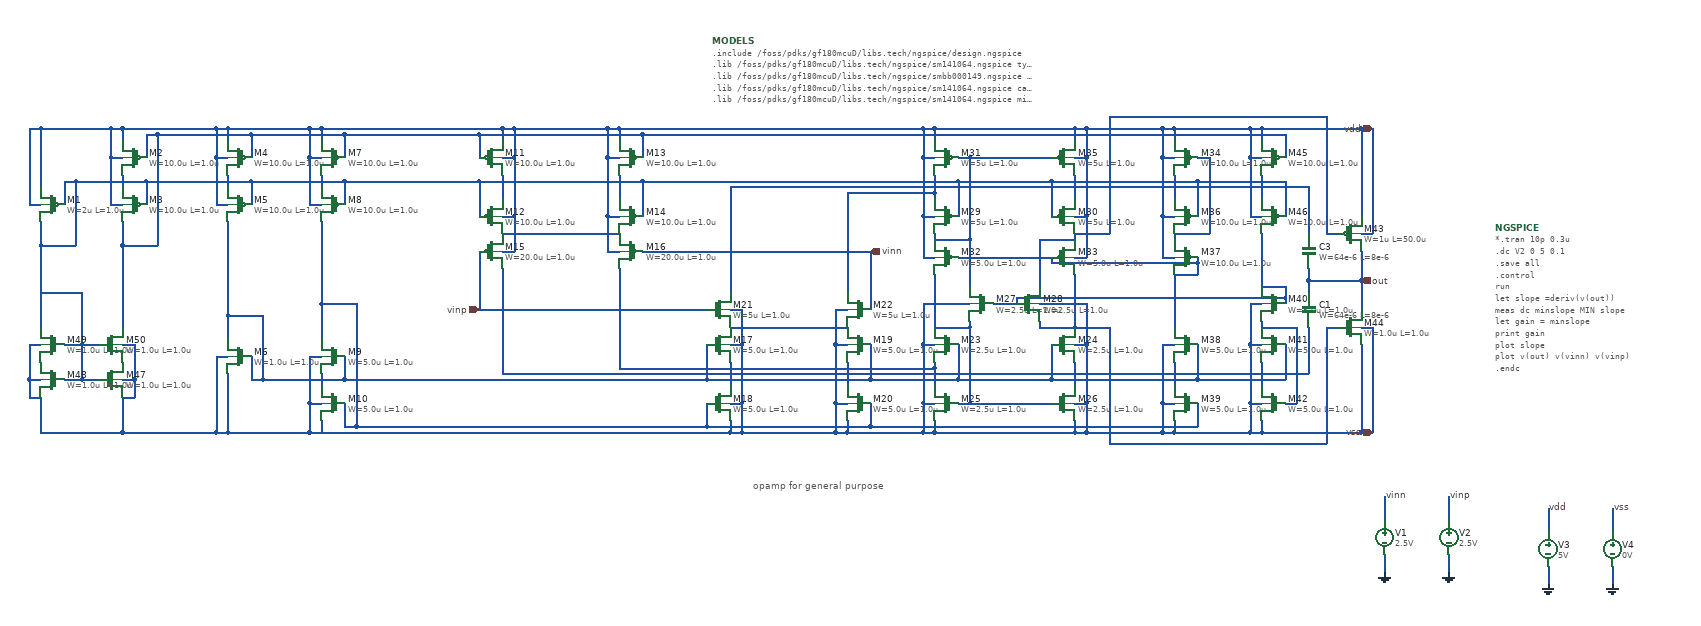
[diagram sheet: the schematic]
v {xschem version=3.4.8RC file_version=1.3}
G {}
K {}
V {}
S {}
F {}
E {}
P 4 1 -1280 220 {}
T {opamp for general purpose} -630 450 2 0 0.4 0.4 {}
N -1060 60 -1040 60 {
lab=vdd}
N -880 60 -860 60 {
lab=vdd}
N -1060 -150 -1060 -130 {
lab=vdd}
N -1060 -100 -1040 -100 {
lab=vdd}
N -1100 -140 -1100 -100 {
lab=#net1}
N -340 320 -340 370 {
lab=vss}
N -340 320 -320 320 {
lab=vss}
N -320 350 -320 370 {
lab=vss}
N -320 -150 -320 -130 {
lab=vdd}
N -340 -100 -320 -100 {
lab=vdd}
N -80 -150 -80 -130 {
lab=vdd}
N -80 -100 -60 -100 {
lab=vdd}
N -60 -100 -60 0 {
lab=vdd}
N -80 320 -60 320 {
lab=vss}
N -80 350 -80 370 {
lab=vss}
N -1100 60 -1100 160 {
lab=vinp}
N -490 160 -470 160 {
lab=vss}
N -670 220 -650 220 {
lab=vss}
N -650 320 -650 370 {
lab=vss}
N -670 320 -650 320 {
lab=vss}
N -670 250 -670 290 {
lab=#net2}
N -670 350 -670 370 {
lab=vss}
N -710 320 -710 360 {
lab=#net3}
N -710 220 -710 280 {
lab=#net4}
N -1060 0 -1040 0 {
lab=vdd}
N -1060 -70 -1060 -30 {
lab=#net5}
N -1100 -60 -1100 0 {
lab=#net6}
N -340 -100 -340 0 {
lab=vdd}
N -340 0 -320 0 {
lab=vdd}
N -320 -40 -320 -30 {
lab=#net7}
N -340 220 -320 220 {
lab=vss}
N -340 220 -340 320 {
lab=vss}
N -320 260 -320 290 {
lab=#net8}
N -80 270 -80 290 {
lab=#net9}
N -80 220 -60 220 {
lab=vss}
N -820 60 -430 60 {
lab=vinn}
N -430 60 -430 160 {
lab=vinn}
N -80 0 -60 0 {
lab=vdd}
N -80 -50 -80 -30 {
lab=#net10}
N -1060 30 -860 30 {
lab=#net11}
N -1100 160 -710 160 {
lab=vinp}
N -670 190 -470 190 {
lab=#net12}
N -320 30 -320 40 {
lab=#net13}
N -340 70 -320 70 {
lab=vdd}
N -340 0 -340 70 {
lab=vdd}
N -260 320 -120 320 {
lab=#net14}
N -60 320 -60 370 {
lab=vss}
N -220 150 -180 150 {
lab=#net15}
N -80 70 -60 70 {
lab=vdd}
N -60 0 -60 70 {
lab=vdd}
N -80 30 -80 40 {
lab=#net16}
N -140 150 -60 150 {
lab=vss}
N -60 150 -60 220 {
lab=vss}
N 410 110 410 160 {
lab=out}
N 410 30 430 30 {
lab=vdd}
N 430 -150 430 30 {
lab=vdd}
N 90 -150 220 -150 {
lab=vdd}
N 410 190 430 190 {
lab=vss}
N 430 190 430 370 {
lab=vss}
N 410 220 410 370 {
lab=vss}
N 410 -150 410 0 {
lab=vdd}
N 70 -100 90 -100 {
lab=vdd}
N 70 -150 70 -100 {
lab=vdd}
N 90 -150 90 -130 {
lab=vdd}
N 90 -70 90 -30 {
lab=#net17}
N 70 0 90 0 {
lab=vdd}
N 70 -100 70 0 {
lab=vdd}
N 90 30 90 40 {
lab=#net18}
N 70 70 90 70 {
lab=vdd}
N 70 0 70 70 {
lab=vdd}
N 70 220 90 220 {
lab=vss}
N 70 320 70 370 {
lab=vss}
N 70 320 90 320 {
lab=vss}
N 90 250 90 290 {
lab=#net19}
N 90 350 90 370 {
lab=vss}
N 130 320 130 360 {
lab=#net3}
N 130 220 130 280 {
lab=#net4}
N 220 -100 240 -100 {
lab=vdd}
N 220 -150 220 -100 {
lab=vdd}
N 240 -150 240 -130 {
lab=vdd}
N 240 -70 240 -30 {
lab=#net20}
N 220 0 240 0 {
lab=vdd}
N 220 -100 220 0 {
lab=vdd}
N 220 220 240 220 {
lab=vss}
N 220 320 220 370 {
lab=vss}
N 220 320 240 320 {
lab=vss}
N 240 250 240 290 {
lab=#net21}
N 240 350 240 370 {
lab=vss}
N 240 180 240 190 {
lab=#net22}
N 220 150 240 150 {
lab=vss}
N 220 150 220 220 {
lab=vss}
N 240 -150 410 -150 {
lab=vdd}
N -860 -150 -860 -130 {
lab=vdd}
N -880 -100 -860 -100 {
lab=vdd}
N -820 -140 -820 -100 {
lab=#net1}
N -880 0 -860 0 {
lab=vdd}
N -860 -70 -860 -30 {
lab=#net23}
N -820 -60 -820 0 {
lab=#net6}
N -490 220 -470 220 {
lab=vss}
N -490 320 -470 320 {
lab=vss}
N -470 250 -470 290 {
lab=#net24}
N -470 350 -470 370 {
lab=vss}
N -430 320 -430 360 {
lab=#net3}
N -430 220 -430 280 {
lab=#net4}
N -670 160 -650 160 {
lab=vss}
N 130 -60 130 0 {
lab=#net6}
N 130 -100 150 -100 {
lab=#net18}
N 150 -100 150 30 {
lab=#net18}
N 90 30 150 30 {
lab=#net18}
N 130 80 130 100 {
lab=#net25}
N 90 100 130 100 {
lab=#net25}
N 90 100 90 190 {
lab=#net25}
N 280 -140 280 -100 {
lab=#net1}
N 280 -60 280 0 {
lab=#net6}
N -120 280 130 280 {
lab=#net4}
N 280 220 280 280 {
lab=#net4}
N 280 320 300 320 {
lab=#net22}
N 300 190 300 320 {
lab=#net22}
N 240 190 300 190 {
lab=#net22}
N 280 140 280 150 {
lab=#net15}
N 240 120 280 120 {
lab=#net15}
N 240 30 240 120 {
lab=#net15}
N -260 -100 -120 -100 {
lab=#net13}
N -280 -60 -280 0 {
lab=#net6}
N -120 -60 -120 0 {
lab=#net6}
N -280 70 -120 70 {
lab=#net25}
N -320 100 -320 190 {
lab=#net14}
N -260 180 -260 190 {
lab=#net14}
N -320 190 -260 190 {
lab=#net14}
N -140 180 -140 190 {
lab=#net26}
N -140 190 -80 190 {
lab=#net26}
N -340 150 -260 150 {
lab=vss}
N -340 150 -340 220 {
lab=vss}
N -80 100 -80 190 {
lab=#net26}
N -260 40 -260 120 {
lab=#net13}
N -320 40 -260 40 {
lab=#net13}
N -140 40 -140 120 {
lab=#net16}
N -140 40 -80 40 {
lab=#net16}
N 130 -60 280 -60 {
lab=#net6}
N -430 360 130 360 {
lab=#net3}
N 130 280 280 280 {
lab=#net4}
N -120 80 130 80 {
lab=#net25}
N -120 70 -120 80 {
lab=#net25}
N -180 140 280 140 {
lab=#net15}
N -180 140 -180 150 {
lab=#net15}
N -1060 90 -1060 270 {
lab=#net9}
N -860 90 -860 260 {
lab=#net8}
N -670 -50 -670 130 {
lab=#net10}
N -470 -40 -470 130 {
lab=#net7}
N -280 220 -280 280 {
lab=#net4}
N -120 220 -120 280 {
lab=#net4}
N -260 190 -260 320 {
lab=#net14}
N -260 -100 -260 40 {
lab=#net13}
N 410 -150 430 -150 {
lab=vdd}
N 350 30 370 30 {
lab=#net16}
N 350 -170 350 30 {
lab=#net16}
N -20 -170 350 -170 {
lab=#net16}
N -20 -170 -20 30 {
lab=#net16}
N -80 30 -20 30 {
lab=#net16}
N 350 190 370 190 {
lab=#net26}
N 350 190 350 390 {
lab=#net26}
N -20 390 350 390 {
lab=#net26}
N -20 190 -20 390 {
lab=#net26}
N -80 190 -20 190 {
lab=#net26}
N -80 270 320 270 {
lab=#net9}
N 320 110 320 130 {
lab=out}
N -670 -50 -80 -50 {
lab=#net10}
N -470 -40 -320 -40 {
lab=#net7}
N -860 260 -320 260 {
lab=#net8}
N -1060 270 -80 270 {
lab=#net9}
N -340 -150 -320 -150 {
lab=vdd}
N -80 -150 -60 -150 {
lab=vdd}
N 410 370 430 370 {
lab=vss}
N -710 280 -430 280 {
lab=#net4}
N -710 360 -430 360 {
lab=#net3}
N -1100 -140 -820 -140 {
lab=#net1}
N -1100 -60 -820 -60 {
lab=#net6}
N -120 -60 130 -60 {
lab=#net6}
N -820 -140 280 -140 {
lab=#net1}
N -880 -150 -860 -150 {
lab=vdd}
N -1250 -140 -1100 -140 {
lab=#net1}
N -1250 -60 -1100 -60 {
lab=#net6}
N -1250 280 -710 280 {
lab=#net4}
N -1230 360 -710 360 {
lab=#net3}
N 320 110 410 110 {
lab=out}
N 320 190 320 270 {
lab=#net9}
N -80 -50 320 -50 {
lab=#net10}
N 320 -50 320 30 {
lab=#net10}
N 320 90 320 110 {
lab=out}
N -880 -100 -880 0 {
lab=vdd}
N -1040 -100 -1040 0 {
lab=vdd}
N -490 320 -490 370 {
lab=vss}
N -650 160 -650 220 {
lab=vss}
N -490 160 -490 220 {
lab=vss}
N -1040 0 -1040 60 {
lab=vdd}
N -880 0 -880 60 {
lab=vdd}
N -1040 -150 -1040 -100 {
lab=vdd}
N -470 370 -340 370 {
lab=vss}
N -340 370 -320 370 {
lab=vss}
N -340 -150 -340 -100 {
lab=vdd}
N -320 -150 -80 -150 {
lab=vdd}
N -60 -150 -60 -100 {
lab=vdd}
N -60 220 -60 320 {
lab=vss}
N -320 370 -80 370 {
lab=vss}
N -670 370 -650 370 {
lab=vss}
N -650 220 -650 320 {
lab=vss}
N -80 370 -60 370 {
lab=vss}
N 240 370 410 370 {
lab=vss}
N -60 -150 70 -150 {
lab=vdd}
N 70 -150 90 -150 {
lab=vdd}
N -60 370 70 370 {
lab=vss}
N 70 220 70 320 {
lab=vss}
N 70 370 90 370 {
lab=vss}
N 220 -150 240 -150 {
lab=vdd}
N 90 370 220 370 {
lab=vss}
N 220 220 220 320 {
lab=vss}
N 220 370 240 370 {
lab=vss}
N -880 -150 -880 -100 {
lab=vdd}
N -490 220 -490 320 {
lab=vss}
N -490 370 -470 370 {
lab=vss}
N -820 -60 -280 -60 {
lab=#net6}
N -280 -60 -120 -60 {
lab=#net6}
N 130 70 130 80 {
lab=#net25}
N 280 120 280 140 {
lab=#net15}
N -430 280 -280 280 {
lab=#net4}
N -280 280 -120 280 {
lab=#net4}
N -280 320 -260 320 {
lab=#net14}
N -280 -100 -260 -100 {
lab=#net13}
N -80 250 -80 270 {
lab=#net9}
N -80 -70 -80 -50 {
lab=#net10}
N -320 -70 -320 -40 {
lab=#net7}
N -320 250 -320 260 {
lab=#net8}
N 410 60 410 110 {
lab=out}
N -650 370 -490 370 {
lab=vss}
N -1060 -150 -1040 -150 {
lab=vdd}
N -860 -150 -340 -150 {
lab=vdd}
N -1040 -150 -880 -150 {
lab=vdd}
N -1390 240 -1370 240 {
lab=vss}
N -1390 320 -1390 370 {
lab=vss}
N -1390 320 -1370 320 {
lab=vss}
N -1370 270 -1370 290 {
lab=#net27}
N -1370 350 -1370 370 {
lab=vss}
N -1370 -150 -1370 -130 {
lab=vdd}
N -1390 -100 -1370 -100 {
lab=vdd}
N -1390 -20 -1370 -20 {
lab=vdd}
N -1390 -100 -1390 -20 {
lab=vdd}
N -1370 -70 -1370 -50 {
lab=#net28}
N -1330 -60 -1330 -20 {
lab=#net6}
N -1330 -140 -1330 -100 {
lab=#net1}
N -1530 -150 -1530 -130 {
lab=vdd}
N -1550 -100 -1530 -100 {
lab=vdd}
N -1550 -20 -1530 -20 {
lab=vdd}
N -1550 -100 -1550 -20 {
lab=vdd}
N -1530 -70 -1530 -50 {
lab=#net29}
N -1490 -60 -1490 -20 {
lab=#net6}
N -1490 -140 -1490 -100 {
lab=#net1}
N -1550 240 -1530 240 {
lab=vss}
N -1550 240 -1550 370 {
lab=vss}
N -1530 270 -1530 370 {
lab=vss}
N -1490 240 -1490 280 {
lab=#net4}
N -1490 280 -1470 280 {
lab=#net4}
N -1530 170 -1470 170 {
lab=#net4}
N -1330 240 -1330 280 {
lab=#net4}
N -1330 320 -1330 360 {
lab=#net3}
N -1330 360 -1310 360 {
lab=#net3}
N -1470 280 -1330 280 {
lab=#net4}
N -1370 150 -1310 150 {
lab=#net3}
N -1530 10 -1530 170 {
lab=#net4}
N -1370 10 -1370 150 {
lab=#net3}
N -1470 170 -1470 280 {
lab=#net4}
N -1310 150 -1310 360 {
lab=#net3}
N -1370 150 -1370 210 {
lab=#net3}
N -1530 170 -1530 210 {
lab=#net4}
N -1330 -140 -1180 -140 {
lab=#net1}
N -1330 -60 -1180 -60 {
lab=#net6}
N -1710 370 -1550 370 {
lab=vss}
N -1710 -150 -1710 -130 {
lab=vdd}
N -1730 -100 -1710 -100 {
lab=vdd}
N -1730 -20 -1710 -20 {
lab=vdd}
N -1730 -100 -1730 -20 {
lab=vdd}
N -1710 -70 -1710 -50 {
lab=#net30}
N -1670 -60 -1670 -20 {
lab=#net6}
N -1670 -140 -1670 -100 {
lab=#net1}
N -1710 50 -1650 50 {
lab=#net1}
N -1710 50 -1710 190 {
lab=#net1}
N -1850 -150 -1850 -50 {
lab=vdd}
N -1870 -20 -1850 -20 {
lab=vdd}
N -1870 -150 -1870 -20 {
lab=vdd}
N -1790 -60 -1670 -60 {
lab=#net6}
N -1810 -60 -1810 -20 {
lab=#net6}
N -1850 50 -1790 50 {
lab=#net6}
N -1850 50 -1850 190 {
lab=#net6}
N -1850 10 -1850 50 {
lab=#net6}
N -1710 10 -1710 50 {
lab=#net1}
N -1790 -60 -1790 50 {
lab=#net6}
N -1650 -140 -1650 50 {
lab=#net1}
N -1850 310 -1850 370 {
lab=vss}
N -1710 310 -1710 370 {
lab=vss}
N -1780 280 -1750 280 {
lab=#net6}
N -1870 280 -1850 280 {
lab=vss}
N -1870 280 -1870 310 {
lab=vss}
N -1870 310 -1850 310 {
lab=vss}
N -1710 280 -1690 280 {
lab=vss}
N -1690 280 -1690 310 {
lab=vss}
N -1710 310 -1690 310 {
lab=vss}
N -1780 220 -1750 220 {
lab=#net6}
N -1780 220 -1780 280 {
lab=#net6}
N -1870 220 -1850 220 {
lab=vss}
N -1870 220 -1870 280 {
lab=vss}
N -1710 220 -1690 220 {
lab=vss}
N -1690 220 -1690 280 {
lab=vss}
N -1780 200 -1780 220 {
lab=#net6}
N -1530 370 -1390 370 {
lab=vss}
N -1390 240 -1390 320 {
lab=vss}
N -1390 370 -1370 370 {
lab=vss}
N -1390 -150 -1370 -150 {
lab=vdd}
N -1390 -150 -1390 -100 {
lab=vdd}
N -1490 -60 -1330 -60 {
lab=#net6}
N -1490 -140 -1330 -140 {
lab=#net1}
N -1550 -150 -1530 -150 {
lab=vdd}
N -1550 -150 -1550 -100 {
lab=vdd}
N -1670 -60 -1490 -60 {
lab=#net6}
N -1650 -140 -1490 -140 {
lab=#net1}
N -1550 370 -1530 370 {
lab=vss}
N -1730 -150 -1710 -150 {
lab=vdd}
N -1730 -150 -1730 -100 {
lab=vdd}
N -1870 -150 -1850 -150 {
lab=vdd}
N -1810 -60 -1790 -60 {
lab=#net6}
N -1670 -140 -1650 -140 {
lab=#net1}
N -1850 370 -1710 370 {
lab=vss}
N -1810 220 -1780 220 {
lab=#net6}
N -1810 280 -1780 280 {
lab=#net6}
N -1530 -150 -1390 -150 {
lab=vdd}
N -1710 -150 -1550 -150 {
lab=vdd}
N -1850 -150 -1730 -150 {
lab=vdd}
N -1850 130 -1780 130 {lab=#net6}
N -1780 130 -1780 200 {lab=#net6}
N -1330 280 -1190 280 {lab=#net4}
N -1310 360 -1190 360 {lab=#net3}
N -1370 -150 -1060 -150 {lab=vdd}
N -1380 370 -670 370 {lab=vss}
N 450 580 450 610 {lab=GND}
N 450 480 450 520 {lab=vinn}
N 560 580 560 610 {lab=GND}
N 560 480 560 520 {lab=vinp}
N 730 600 730 630 {lab=GND}
N 730 500 730 540 {lab=vdd}
N 840 600 840 630 {lab=GND}
N 840 500 840 540 {lab=vss}
C {devices/opin.sym} 410 110 0 0 {name=p1 lab=out}
C {devices/iopin.sym} 430 -150 0 0 {name=p3 lab=vdd}
C {devices/iopin.sym} 430 370 0 0 {name=p4 lab=vss}
C {devices/ipin.sym} -1100 160 0 0 {name=p2 lab=vinp}
C {devices/ipin.sym} -430 60 0 1 {name=p5 lab=vinn}
C {symbols/pfet_06v0.sym} -1080 -100 0 0 {name=M11
L=1.0u
W=10.0u
nf=1
m=1
ad="'int((nf+1)/2) * W/nf * 0.18u'"
pd="'2*int((nf+1)/2) * (W/nf + 0.18u)'"
as="'int((nf+2)/2) * W/nf * 0.18u'"
ps="'2*int((nf+2)/2) * (W/nf + 0.18u)'"
nrd="'0.18u / W'" nrs="'0.18u / W'"
sa=0 sb=0 sd=0
model=pfet_06v0
spiceprefix=X
}
C {symbols/pfet_06v0.sym} -1080 0 0 0 {name=M12
L=1.0u
W=10.0u
nf=1
m=1
ad="'int((nf+1)/2) * W/nf * 0.18u'"
pd="'2*int((nf+1)/2) * (W/nf + 0.18u)'"
as="'int((nf+2)/2) * W/nf * 0.18u'"
ps="'2*int((nf+2)/2) * (W/nf + 0.18u)'"
nrd="'0.18u / W'" nrs="'0.18u / W'"
sa=0 sb=0 sd=0
model=pfet_06v0
spiceprefix=X
}
C {symbols/pfet_06v0.sym} -840 -100 0 1 {name=M13
L=1.0u
W=10.0u
nf=1
m=1
ad="'int((nf+1)/2) * W/nf * 0.18u'"
pd="'2*int((nf+1)/2) * (W/nf + 0.18u)'"
as="'int((nf+2)/2) * W/nf * 0.18u'"
ps="'2*int((nf+2)/2) * (W/nf + 0.18u)'"
nrd="'0.18u / W'" nrs="'0.18u / W'"
sa=0 sb=0 sd=0
model=pfet_06v0
spiceprefix=X
}
C {symbols/pfet_06v0.sym} -840 0 0 1 {name=M14
L=1.0u
W=10.0u
nf=1
m=1
ad="'int((nf+1)/2) * W/nf * 0.18u'"
pd="'2*int((nf+1)/2) * (W/nf + 0.18u)'"
as="'int((nf+2)/2) * W/nf * 0.18u'"
ps="'2*int((nf+2)/2) * (W/nf + 0.18u)'"
nrd="'0.18u / W'" nrs="'0.18u / W'"
sa=0 sb=0 sd=0
model=pfet_06v0
spiceprefix=X
}
C {symbols/pfet_06v0.sym} -1080 60 0 0 {name=M15
L=1.0u
W=20.0u
nf=2
m=1
ad="'int((nf+1)/2) * W/nf * 0.18u'"
pd="'2*int((nf+1)/2) * (W/nf + 0.18u)'"
as="'int((nf+2)/2) * W/nf * 0.18u'"
ps="'2*int((nf+2)/2) * (W/nf + 0.18u)'"
nrd="'0.18u / W'" nrs="'0.18u / W'"
sa=0 sb=0 sd=0
model=pfet_06v0
spiceprefix=X
}
C {symbols/pfet_06v0.sym} -840 60 0 1 {name=M16
L=1.0u
W=20.0u
nf=2
m=1
ad="'int((nf+1)/2) * W/nf * 0.18u'"
pd="'2*int((nf+1)/2) * (W/nf + 0.18u)'"
as="'int((nf+2)/2) * W/nf * 0.18u'"
ps="'2*int((nf+2)/2) * (W/nf + 0.18u)'"
nrd="'0.18u / W'" nrs="'0.18u / W'"
sa=0 sb=0 sd=0
model=pfet_06v0
spiceprefix=X
}
C {symbols/nfet_06v0.sym} -690 220 0 0 {name=M17
L=1.0u
W=5.0u
nf=1
m=1
ad="'int((nf+1)/2) * W/nf * 0.18u'"
pd="'2*int((nf+1)/2) * (W/nf + 0.18u)'"
as="'int((nf+2)/2) * W/nf * 0.18u'"
ps="'2*int((nf+2)/2) * (W/nf + 0.18u)'"
nrd="'0.18u / W'" nrs="'0.18u / W'"
sa=0 sb=0 sd=0
model=nfet_06v0
spiceprefix=X
}
C {symbols/nfet_06v0.sym} -690 320 0 0 {name=M18
L=1.0u
W=5.0u
nf=1
m=1
ad="'int((nf+1)/2) * W/nf * 0.18u'"
pd="'2*int((nf+1)/2) * (W/nf + 0.18u)'"
as="'int((nf+2)/2) * W/nf * 0.18u'"
ps="'2*int((nf+2)/2) * (W/nf + 0.18u)'"
nrd="'0.18u / W'" nrs="'0.18u / W'"
sa=0 sb=0 sd=0
model=nfet_06v0
spiceprefix=X
}
C {symbols/nfet_06v0.sym} -450 220 0 1 {name=M19
L=1.0u
W=5.0u
nf=1
m=1
ad="'int((nf+1)/2) * W/nf * 0.18u'"
pd="'2*int((nf+1)/2) * (W/nf + 0.18u)'"
as="'int((nf+2)/2) * W/nf * 0.18u'"
ps="'2*int((nf+2)/2) * (W/nf + 0.18u)'"
nrd="'0.18u / W'" nrs="'0.18u / W'"
sa=0 sb=0 sd=0
model=nfet_06v0
spiceprefix=X
}
C {symbols/nfet_06v0.sym} -450 320 0 1 {name=M20
L=1.0u
W=5.0u
nf=1
m=1
ad="'int((nf+1)/2) * W/nf * 0.18u'"
pd="'2*int((nf+1)/2) * (W/nf + 0.18u)'"
as="'int((nf+2)/2) * W/nf * 0.18u'"
ps="'2*int((nf+2)/2) * (W/nf + 0.18u)'"
nrd="'0.18u / W'" nrs="'0.18u / W'"
sa=0 sb=0 sd=0
model=nfet_06v0
spiceprefix=X
}
C {symbols/nfet_06v0.sym} -690 160 0 0 {name=M21
L=1.0u
W=5u
nf=2
m=1
ad="'int((nf+1)/2) * W/nf * 0.18u'"
pd="'2*int((nf+1)/2) * (W/nf + 0.18u)'"
as="'int((nf+2)/2) * W/nf * 0.18u'"
ps="'2*int((nf+2)/2) * (W/nf + 0.18u)'"
nrd="'0.18u / W'" nrs="'0.18u / W'"
sa=0 sb=0 sd=0
model=nfet_06v0
spiceprefix=X
}
C {symbols/nfet_06v0.sym} -450 160 0 1 {name=M22
L=1.0u
W=5u
nf=2
m=1
ad="'int((nf+1)/2) * W/nf * 0.18u'"
pd="'2*int((nf+1)/2) * (W/nf + 0.18u)'"
as="'int((nf+2)/2) * W/nf * 0.18u'"
ps="'2*int((nf+2)/2) * (W/nf + 0.18u)'"
nrd="'0.18u / W'" nrs="'0.18u / W'"
sa=0 sb=0 sd=0
model=nfet_06v0
spiceprefix=X
}
C {symbols/pfet_06v0.sym} -300 0 0 1 {name=M29
L=1.0u
W=5u
nf=2
m=1
ad="'int((nf+1)/2) * W/nf * 0.18u'"
pd="'2*int((nf+1)/2) * (W/nf + 0.18u)'"
as="'int((nf+2)/2) * W/nf * 0.18u'"
ps="'2*int((nf+2)/2) * (W/nf + 0.18u)'"
nrd="'0.18u / W'" nrs="'0.18u / W'"
sa=0 sb=0 sd=0
model=pfet_06v0
spiceprefix=X
}
C {symbols/pfet_06v0.sym} -100 0 0 0 {name=M30
L=1.0u
W=5u
nf=2
m=1
ad="'int((nf+1)/2) * W/nf * 0.18u'"
pd="'2*int((nf+1)/2) * (W/nf + 0.18u)'"
as="'int((nf+2)/2) * W/nf * 0.18u'"
ps="'2*int((nf+2)/2) * (W/nf + 0.18u)'"
nrd="'0.18u / W'" nrs="'0.18u / W'"
sa=0 sb=0 sd=0
model=pfet_06v0
spiceprefix=X
}
C {symbols/pfet_06v0.sym} -300 -100 0 1 {name=M31
L=1.0u
W=5u
nf=4
m=1
ad="'int((nf+1)/2) * W/nf * 0.18u'"
pd="'2*int((nf+1)/2) * (W/nf + 0.18u)'"
as="'int((nf+2)/2) * W/nf * 0.18u'"
ps="'2*int((nf+2)/2) * (W/nf + 0.18u)'"
nrd="'0.18u / W'" nrs="'0.18u / W'"
sa=0 sb=0 sd=0
model=pfet_06v0
spiceprefix=X
}
C {symbols/pfet_06v0.sym} -100 -100 0 0 {name=M35
L=1.0u
W=5u
nf=4
m=1
ad="'int((nf+1)/2) * W/nf * 0.18u'"
pd="'2*int((nf+1)/2) * (W/nf + 0.18u)'"
as="'int((nf+2)/2) * W/nf * 0.18u'"
ps="'2*int((nf+2)/2) * (W/nf + 0.18u)'"
nrd="'0.18u / W'" nrs="'0.18u / W'"
sa=0 sb=0 sd=0
model=pfet_06v0
spiceprefix=X
}
C {symbols/pfet_06v0.sym} -300 70 0 1 {name=M32
L=1.0u
W=5.0u
nf=2
m=1
ad="'int((nf+1)/2) * W/nf * 0.18u'"
pd="'2*int((nf+1)/2) * (W/nf + 0.18u)'"
as="'int((nf+2)/2) * W/nf * 0.18u'"
ps="'2*int((nf+2)/2) * (W/nf + 0.18u)'"
nrd="'0.18u / W'" nrs="'0.18u / W'"
sa=0 sb=0 sd=0
model=pfet_06v0
spiceprefix=X
}
C {symbols/pfet_06v0.sym} -100 70 0 0 {name=M33
L=1.0u
W=5.0u
nf=2
m=1
ad="'int((nf+1)/2) * W/nf * 0.18u'"
pd="'2*int((nf+1)/2) * (W/nf + 0.18u)'"
as="'int((nf+2)/2) * W/nf * 0.18u'"
ps="'2*int((nf+2)/2) * (W/nf + 0.18u)'"
nrd="'0.18u / W'" nrs="'0.18u / W'"
sa=0 sb=0 sd=0
model=pfet_06v0
spiceprefix=X
}
C {symbols/nfet_06v0.sym} -300 220 0 1 {name=M23
L=1.0u
W=2.5u
nf=2
m=1
ad="'int((nf+1)/2) * W/nf * 0.18u'"
pd="'2*int((nf+1)/2) * (W/nf + 0.18u)'"
as="'int((nf+2)/2) * W/nf * 0.18u'"
ps="'2*int((nf+2)/2) * (W/nf + 0.18u)'"
nrd="'0.18u / W'" nrs="'0.18u / W'"
sa=0 sb=0 sd=0
model=nfet_06v0
spiceprefix=X
}
C {symbols/nfet_06v0.sym} -100 220 0 0 {name=M24
L=1.0u
W=2.5u
nf=2
m=1
ad="'int((nf+1)/2) * W/nf * 0.18u'"
pd="'2*int((nf+1)/2) * (W/nf + 0.18u)'"
as="'int((nf+2)/2) * W/nf * 0.18u'"
ps="'2*int((nf+2)/2) * (W/nf + 0.18u)'"
nrd="'0.18u / W'" nrs="'0.18u / W'"
sa=0 sb=0 sd=0
model=nfet_06v0
spiceprefix=X
}
C {symbols/nfet_06v0.sym} -300 320 0 1 {name=M25
L=1.0u
W=2.5u
nf=4
m=1
ad="'int((nf+1)/2) * W/nf * 0.18u'"
pd="'2*int((nf+1)/2) * (W/nf + 0.18u)'"
as="'int((nf+2)/2) * W/nf * 0.18u'"
ps="'2*int((nf+2)/2) * (W/nf + 0.18u)'"
nrd="'0.18u / W'" nrs="'0.18u / W'"
sa=0 sb=0 sd=0
model=nfet_06v0
spiceprefix=X
}
C {symbols/nfet_06v0.sym} -100 320 0 0 {name=M26
L=1.0u
W=2.5u
nf=4
m=1
ad="'int((nf+1)/2) * W/nf * 0.18u'"
pd="'2*int((nf+1)/2) * (W/nf + 0.18u)'"
as="'int((nf+2)/2) * W/nf * 0.18u'"
ps="'2*int((nf+2)/2) * (W/nf + 0.18u)'"
nrd="'0.18u / W'" nrs="'0.18u / W'"
sa=0 sb=0 sd=0
model=nfet_06v0
spiceprefix=X
}
C {symbols/nfet_06v0.sym} -240 150 0 1 {name=M27
L=1.0u
W=2.5u
nf=1
m=1
ad="'int((nf+1)/2) * W/nf * 0.18u'"
pd="'2*int((nf+1)/2) * (W/nf + 0.18u)'"
as="'int((nf+2)/2) * W/nf * 0.18u'"
ps="'2*int((nf+2)/2) * (W/nf + 0.18u)'"
nrd="'0.18u / W'" nrs="'0.18u / W'"
sa=0 sb=0 sd=0
model=nfet_06v0
spiceprefix=X
}
C {symbols/nfet_06v0.sym} -160 150 0 0 {name=M28
L=1.0u
W=2.5u
nf=1
m=1
ad="'int((nf+1)/2) * W/nf * 0.18u'"
pd="'2*int((nf+1)/2) * (W/nf + 0.18u)'"
as="'int((nf+2)/2) * W/nf * 0.18u'"
ps="'2*int((nf+2)/2) * (W/nf + 0.18u)'"
nrd="'0.18u / W'" nrs="'0.18u / W'"
sa=0 sb=0 sd=0
model=nfet_06v0
spiceprefix=X
}
C {symbols/pfet_06v0.sym} 110 -100 0 1 {name=M34
L=1.0u
W=10.0u
nf=1
m=1
ad="'int((nf+1)/2) * W/nf * 0.18u'"
pd="'2*int((nf+1)/2) * (W/nf + 0.18u)'"
as="'int((nf+2)/2) * W/nf * 0.18u'"
ps="'2*int((nf+2)/2) * (W/nf + 0.18u)'"
nrd="'0.18u / W'" nrs="'0.18u / W'"
sa=0 sb=0 sd=0
model=pfet_06v0
spiceprefix=X
}
C {symbols/pfet_06v0.sym} 110 0 0 1 {name=M36
L=1.0u
W=10.0u
nf=1
m=1
ad="'int((nf+1)/2) * W/nf * 0.18u'"
pd="'2*int((nf+1)/2) * (W/nf + 0.18u)'"
as="'int((nf+2)/2) * W/nf * 0.18u'"
ps="'2*int((nf+2)/2) * (W/nf + 0.18u)'"
nrd="'0.18u / W'" nrs="'0.18u / W'"
sa=0 sb=0 sd=0
model=pfet_06v0
spiceprefix=X
}
C {symbols/pfet_06v0.sym} 110 70 0 1 {name=M37
L=1.0u
W=10.0u
nf=1
m=1
ad="'int((nf+1)/2) * W/nf * 0.18u'"
pd="'2*int((nf+1)/2) * (W/nf + 0.18u)'"
as="'int((nf+2)/2) * W/nf * 0.18u'"
ps="'2*int((nf+2)/2) * (W/nf + 0.18u)'"
nrd="'0.18u / W'" nrs="'0.18u / W'"
sa=0 sb=0 sd=0
model=pfet_06v0
spiceprefix=X
}
C {symbols/nfet_06v0.sym} 110 220 0 1 {name=M38
L=1.0u
W=5.0u
nf=1
m=1
ad="'int((nf+1)/2) * W/nf * 0.18u'"
pd="'2*int((nf+1)/2) * (W/nf + 0.18u)'"
as="'int((nf+2)/2) * W/nf * 0.18u'"
ps="'2*int((nf+2)/2) * (W/nf + 0.18u)'"
nrd="'0.18u / W'" nrs="'0.18u / W'"
sa=0 sb=0 sd=0
model=nfet_06v0
spiceprefix=X
}
C {symbols/nfet_06v0.sym} 110 320 0 1 {name=M39
L=1.0u
W=5.0u
nf=1
m=1
ad="'int((nf+1)/2) * W/nf * 0.18u'"
pd="'2*int((nf+1)/2) * (W/nf + 0.18u)'"
as="'int((nf+2)/2) * W/nf * 0.18u'"
ps="'2*int((nf+2)/2) * (W/nf + 0.18u)'"
nrd="'0.18u / W'" nrs="'0.18u / W'"
sa=0 sb=0 sd=0
model=nfet_06v0
spiceprefix=X
}
C {symbols/pfet_06v0.sym} 260 -100 0 1 {name=M45
L=1.0u
W=10.0u
nf=1
m=1
ad="'int((nf+1)/2) * W/nf * 0.18u'"
pd="'2*int((nf+1)/2) * (W/nf + 0.18u)'"
as="'int((nf+2)/2) * W/nf * 0.18u'"
ps="'2*int((nf+2)/2) * (W/nf + 0.18u)'"
nrd="'0.18u / W'" nrs="'0.18u / W'"
sa=0 sb=0 sd=0
model=pfet_06v0
spiceprefix=X
}
C {symbols/pfet_06v0.sym} 260 0 0 1 {name=M46
L=1.0u
W=10.0u
nf=1
m=1
ad="'int((nf+1)/2) * W/nf * 0.18u'"
pd="'2*int((nf+1)/2) * (W/nf + 0.18u)'"
as="'int((nf+2)/2) * W/nf * 0.18u'"
ps="'2*int((nf+2)/2) * (W/nf + 0.18u)'"
nrd="'0.18u / W'" nrs="'0.18u / W'"
sa=0 sb=0 sd=0
model=pfet_06v0
spiceprefix=X
}
C {symbols/nfet_06v0.sym} 260 150 0 1 {name=M40
L=1.0u
W=5.0u
nf=1
m=1
ad="'int((nf+1)/2) * W/nf * 0.18u'"
pd="'2*int((nf+1)/2) * (W/nf + 0.18u)'"
as="'int((nf+2)/2) * W/nf * 0.18u'"
ps="'2*int((nf+2)/2) * (W/nf + 0.18u)'"
nrd="'0.18u / W'" nrs="'0.18u / W'"
sa=0 sb=0 sd=0
model=nfet_06v0
spiceprefix=X
}
C {symbols/nfet_06v0.sym} 260 220 0 1 {name=M41
L=1.0u
W=5.0u
nf=1
m=1
ad="'int((nf+1)/2) * W/nf * 0.18u'"
pd="'2*int((nf+1)/2) * (W/nf + 0.18u)'"
as="'int((nf+2)/2) * W/nf * 0.18u'"
ps="'2*int((nf+2)/2) * (W/nf + 0.18u)'"
nrd="'0.18u / W'" nrs="'0.18u / W'"
sa=0 sb=0 sd=0
model=nfet_06v0
spiceprefix=X
}
C {symbols/nfet_06v0.sym} 260 320 0 1 {name=M42
L=1.0u
W=5.0u
nf=1
m=1
ad="'int((nf+1)/2) * W/nf * 0.18u'"
pd="'2*int((nf+1)/2) * (W/nf + 0.18u)'"
as="'int((nf+2)/2) * W/nf * 0.18u'"
ps="'2*int((nf+2)/2) * (W/nf + 0.18u)'"
nrd="'0.18u / W'" nrs="'0.18u / W'"
sa=0 sb=0 sd=0
model=nfet_06v0
spiceprefix=X
}
C {symbols/pfet_06v0.sym} 390 30 0 0 {name=M43
L=50.0u
W=1u
nf=1
m=1
ad="'int((nf+1)/2) * W/nf * 0.18u'"
pd="'2*int((nf+1)/2) * (W/nf + 0.18u)'"
as="'int((nf+2)/2) * W/nf * 0.18u'"
ps="'2*int((nf+2)/2) * (W/nf + 0.18u)'"
nrd="'0.18u / W'" nrs="'0.18u / W'"
sa=0 sb=0 sd=0
model=pfet_06v0
spiceprefix=X
}
C {symbols/nfet_06v0.sym} 390 190 0 0 {name=M44
L=1.0u
W=1.0u
nf=14
m=1
ad="'int((nf+1)/2) * W/nf * 0.18u'"
pd="'2*int((nf+1)/2) * (W/nf + 0.18u)'"
as="'int((nf+2)/2) * W/nf * 0.18u'"
ps="'2*int((nf+2)/2) * (W/nf + 0.18u)'"
nrd="'0.18u / W'" nrs="'0.18u / W'"
sa=0 sb=0 sd=0
model=nfet_06v0
spiceprefix=X
}
C {symbols/cap_mim_2f0fF.sym} 320 60 0 0 {name=C3
W=64e-6
L=8e-6
model=cap_mim_2f0fF
spiceprefix=X
m=1}
C {symbols/cap_mim_2f0fF.sym} 320 160 0 0 {name=C1
W=64e-6
L=8e-6
model=cap_mim_2f0fF
spiceprefix=X
m=1}
C {symbols/pfet_06v0.sym} -1510 -100 0 1 {name=M4
L=1.0u
W=10.0u
nf=1
m=1
ad="'int((nf+1)/2) * W/nf * 0.18u'"
pd="'2*int((nf+1)/2) * (W/nf + 0.18u)'"
as="'int((nf+2)/2) * W/nf * 0.18u'"
ps="'2*int((nf+2)/2) * (W/nf + 0.18u)'"
nrd="'0.18u / W'" nrs="'0.18u / W'"
sa=0 sb=0 sd=0
model=pfet_06v0
spiceprefix=X
}
C {symbols/pfet_06v0.sym} -1510 -20 0 1 {name=M5
L=1.0u
W=10.0u
nf=1
m=1
ad="'int((nf+1)/2) * W/nf * 0.18u'"
pd="'2*int((nf+1)/2) * (W/nf + 0.18u)'"
as="'int((nf+2)/2) * W/nf * 0.18u'"
ps="'2*int((nf+2)/2) * (W/nf + 0.18u)'"
nrd="'0.18u / W'" nrs="'0.18u / W'"
sa=0 sb=0 sd=0
model=pfet_06v0
spiceprefix=X
}
C {symbols/nfet_06v0.sym} -1510 240 0 1 {name=M6
L=1.0u
W=1.0u
nf=1
m=1
ad="'int((nf+1)/2) * W/nf * 0.18u'"
pd="'2*int((nf+1)/2) * (W/nf + 0.18u)'"
as="'int((nf+2)/2) * W/nf * 0.18u'"
ps="'2*int((nf+2)/2) * (W/nf + 0.18u)'"
nrd="'0.18u / W'" nrs="'0.18u / W'"
sa=0 sb=0 sd=0
model=nfet_06v0
spiceprefix=X
}
C {symbols/pfet_06v0.sym} -1350 -100 0 1 {name=M7
L=1.0u
W=10.0u
nf=1
m=1
ad="'int((nf+1)/2) * W/nf * 0.18u'"
pd="'2*int((nf+1)/2) * (W/nf + 0.18u)'"
as="'int((nf+2)/2) * W/nf * 0.18u'"
ps="'2*int((nf+2)/2) * (W/nf + 0.18u)'"
nrd="'0.18u / W'" nrs="'0.18u / W'"
sa=0 sb=0 sd=0
model=pfet_06v0
spiceprefix=X
}
C {symbols/pfet_06v0.sym} -1350 -20 0 1 {name=M8
L=1.0u
W=10.0u
nf=1
m=1
ad="'int((nf+1)/2) * W/nf * 0.18u'"
pd="'2*int((nf+1)/2) * (W/nf + 0.18u)'"
as="'int((nf+2)/2) * W/nf * 0.18u'"
ps="'2*int((nf+2)/2) * (W/nf + 0.18u)'"
nrd="'0.18u / W'" nrs="'0.18u / W'"
sa=0 sb=0 sd=0
model=pfet_06v0
spiceprefix=X
}
C {symbols/nfet_06v0.sym} -1350 240 0 1 {name=M9
L=1.0u
W=5.0u
nf=1
m=1
ad="'int((nf+1)/2) * W/nf * 0.18u'"
pd="'2*int((nf+1)/2) * (W/nf + 0.18u)'"
as="'int((nf+2)/2) * W/nf * 0.18u'"
ps="'2*int((nf+2)/2) * (W/nf + 0.18u)'"
nrd="'0.18u / W'" nrs="'0.18u / W'"
sa=0 sb=0 sd=0
model=nfet_06v0
spiceprefix=X
}
C {symbols/nfet_06v0.sym} -1350 320 0 1 {name=M10
L=1.0u
W=5.0u
nf=1
m=1
ad="'int((nf+1)/2) * W/nf * 0.18u'"
pd="'2*int((nf+1)/2) * (W/nf + 0.18u)'"
as="'int((nf+2)/2) * W/nf * 0.18u'"
ps="'2*int((nf+2)/2) * (W/nf + 0.18u)'"
nrd="'0.18u / W'" nrs="'0.18u / W'"
sa=0 sb=0 sd=0
model=nfet_06v0
spiceprefix=X
}
C {symbols/pfet_06v0.sym} -1830 -20 0 1 {name=M1
L=1.0u
W=2u
nf=1
m=1
ad="'int((nf+1)/2) * W/nf * 0.18u'"
pd="'2*int((nf+1)/2) * (W/nf + 0.18u)'"
as="'int((nf+2)/2) * W/nf * 0.18u'"
ps="'2*int((nf+2)/2) * (W/nf + 0.18u)'"
nrd="'0.18u / W'" nrs="'0.18u / W'"
sa=0 sb=0 sd=0
model=pfet_06v0
spiceprefix=X
}
C {symbols/pfet_06v0.sym} -1690 -100 0 1 {name=M2
L=1.0u
W=10.0u
nf=1
m=1
ad="'int((nf+1)/2) * W/nf * 0.18u'"
pd="'2*int((nf+1)/2) * (W/nf + 0.18u)'"
as="'int((nf+2)/2) * W/nf * 0.18u'"
ps="'2*int((nf+2)/2) * (W/nf + 0.18u)'"
nrd="'0.18u / W'" nrs="'0.18u / W'"
sa=0 sb=0 sd=0
model=pfet_06v0
spiceprefix=X
}
C {symbols/pfet_06v0.sym} -1690 -20 0 1 {name=M3
L=1.0u
W=10.0u
nf=1
m=1
ad="'int((nf+1)/2) * W/nf * 0.18u'"
pd="'2*int((nf+1)/2) * (W/nf + 0.18u)'"
as="'int((nf+2)/2) * W/nf * 0.18u'"
ps="'2*int((nf+2)/2) * (W/nf + 0.18u)'"
nrd="'0.18u / W'" nrs="'0.18u / W'"
sa=0 sb=0 sd=0
model=pfet_06v0
spiceprefix=X
}
C {symbols/nfet_06v0.sym} -1730 280 0 0 {name=M47
L=1.0u
W=1.0u
nf=1
m=1
ad="'int((nf+1)/2) * W/nf * 0.18u'"
pd="'2*int((nf+1)/2) * (W/nf + 0.18u)'"
as="'int((nf+2)/2) * W/nf * 0.18u'"
ps="'2*int((nf+2)/2) * (W/nf + 0.18u)'"
nrd="'0.18u / W'" nrs="'0.18u / W'"
sa=0 sb=0 sd=0
model=nfet_06v0
spiceprefix=X
}
C {symbols/nfet_06v0.sym} -1830 280 0 1 {name=M48
L=1.0u
W=1.0u
nf=1
m=1
ad="'int((nf+1)/2) * W/nf * 0.18u'"
pd="'2*int((nf+1)/2) * (W/nf + 0.18u)'"
as="'int((nf+2)/2) * W/nf * 0.18u'"
ps="'2*int((nf+2)/2) * (W/nf + 0.18u)'"
nrd="'0.18u / W'" nrs="'0.18u / W'"
sa=0 sb=0 sd=0
model=nfet_06v0
spiceprefix=X
}
C {symbols/nfet_06v0.sym} -1830 220 0 1 {name=M49
L=1.0u
W=1.0u
nf=1
m=1
ad="'int((nf+1)/2) * W/nf * 0.18u'"
pd="'2*int((nf+1)/2) * (W/nf + 0.18u)'"
as="'int((nf+2)/2) * W/nf * 0.18u'"
ps="'2*int((nf+2)/2) * (W/nf + 0.18u)'"
nrd="'0.18u / W'" nrs="'0.18u / W'"
sa=0 sb=0 sd=0
model=nfet_06v0
spiceprefix=X
}
C {symbols/nfet_06v0.sym} -1730 220 0 0 {name=M50
L=1.0u
W=1.0u
nf=1
m=1
ad="'int((nf+1)/2) * W/nf * 0.18u'"
pd="'2*int((nf+1)/2) * (W/nf + 0.18u)'"
as="'int((nf+2)/2) * W/nf * 0.18u'"
ps="'2*int((nf+2)/2) * (W/nf + 0.18u)'"
nrd="'0.18u / W'" nrs="'0.18u / W'"
sa=0 sb=0 sd=0
model=nfet_06v0
spiceprefix=X
}
C {vsource.sym} 450 550 0 0 {name=V1 value=2.5V savecurrent=false}
C {gnd.sym} 450 610 0 0 {name=l6 lab=GND}
C {vsource.sym} 560 550 0 0 {name=V2 value=2.5V savecurrent=false}
C {gnd.sym} 560 610 0 0 {name=l5 lab=GND}
C {lab_pin.sym} 560 480 2 0 {name=p11 sig_type=std_logic lab=vinp}
C {lab_pin.sym} 450 480 2 0 {name=p6 sig_type=std_logic lab=vinn
}
C {vsource.sym} 730 570 0 0 {name=V3 value=5V savecurrent=false}
C {gnd.sym} 730 630 0 0 {name=l1 lab=GND}
C {lab_pin.sym} 730 500 2 0 {name=p7 sig_type=std_logic lab=vdd}
C {vsource.sym} 840 570 0 0 {name=V4 value=0V savecurrent=false}
C {gnd.sym} 840 630 0 0 {name=l2 lab=GND}
C {lab_pin.sym} 840 500 2 0 {name=p8 sig_type=std_logic lab=vss}
C {code_shown.sym} -700 -300 0 0 {name=MODELS only_toplevel=false value=".include /foss/pdks/gf180mcuD/libs.tech/ngspice/design.ngspice
.lib /foss/pdks/gf180mcuD/libs.tech/ngspice/sm141064.ngspice typical
.lib /foss/pdks/gf180mcuD/libs.tech/ngspice/smbb000149.ngspice typical
.lib /foss/pdks/gf180mcuD/libs.tech/ngspice/sm141064.ngspice cap_mim
.lib /foss/pdks/gf180mcuD/libs.tech/ngspice/sm141064.ngspice mimcap_typical"}
C {code_shown.sym} 640 20 0 0 {name=NGSPICE only_toplevel=false value="
*.tran 10p 0.3u
.dc V2 0 5 0.1 
.save all
.control
run
let slope =deriv(v(out))
meas dc minslope MIN slope
let gain = minslope
print gain
plot slope
plot v(out) v(vinn) v(vinp)

.endc"

}
